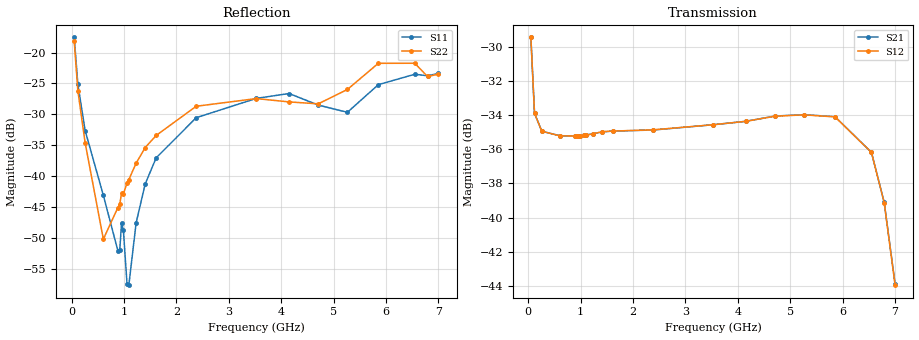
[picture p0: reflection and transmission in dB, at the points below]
! Integrated Device Technology
! Corporate Headquarters
! 6024 Silver Creek Valley Road
! San Jose, CA 95138  USA
! Phone:  1-408-284-8200
! Toll Free:  1-800-223-1366
! Webpage:  http://www.idt.com/
! Timing and RF Division
! 515 Groton Road, Suite 102
! Westford, MA 01886-6024
! Device:  F2258
! Description: Voltage Variable RF Attenuator
! Frequency:  50.0 -  6000.00 MHz
! Package:  3x3 mm Thin QFN Plastic Package: 16 pin
! Ports:  2 RF, 2 DC
!  Pin  1  = NC
!  Pin  2  = NC
!  Pin  3  = RF2  = Port 2
!  Pin  4  = GND
!  Pin  5  = Vdd
!  Pin  6  = NC
!  Pin  7  = VCTRL
!  Pin  8  = NC
!  Pin  9  = GND
!  Pin 10  = RF1  = Port 1
!  Pin 11  = NC
!  Pin 12  = NC
!  Pin 13  = NC
!  Pin 14  = NC
!  Pin 15  = NC
!  Pin 16  = NC
! Vcntrl:  2.090 Volts
! Vdd:  +3.300 Volts
! Current:  1.150 mA
! Data:  The device was measured on a the F2258 evaluation board which has
!  individual transmission lines to the RF pins.  Data was collected
!  using a calibrated network analyzer.  The evaluation board was
!  de-embedded using a TRL calibration technique.
!  The reference plane is the edge of the package pin.
! Misc:  SN 10
!  Action Tracker AT0285
! Date Measured:  2014-12-10
! Date:  2016-01-13  MJV
! Note:
!  Integrated Device Technology supplies this data as a sample of measured
!  data at the package pin for this product.  Your particular data for this
!  product may vary.
!  Data was taken at 25 degrees C.
!  Integrated Device Technology reserves the right to change this data at anytime.
!Freq_(GHz)  S11M_(dB)  S11P_(deg)  S21M_(dB)  S21P_(deg)  S12M_(dB)  S12P_(deg)  S22M_(dB)  S22P_(deg)
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# GHz S dB R 50
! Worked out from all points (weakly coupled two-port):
!   201 points, 50 MHz to 7 GHz, reference 50 ohm
!   highest |S21| = -29.44 dB at 50 MHz (marker M1); lowest = -43.9 dB at 7 GHz (marker M2)
!   lowest |S11| = -57.6 dB at 1.093 GHz (marker M3), VSWR 1.00, Z = 49.9 + j0.114 ohm
!   |S11| at or under -10 dB: start of sweep to end of sweep
!   |S22| runs from -50.2 to -18.2 dB; largest |S21 - S12| = 7.9e-05
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0.05  -17.55 -111.0  -29.44 -67.6  -29.44 -67.6  -18.16 -109.8
0.1195  -25.11 -106.8  -33.89 -36.3  -33.89 -36.3  -26.16 -100.6
0.2585  -32.61 -111.9  -34.94 -18.6  -34.94 -18.6  -34.58 -94.6
0.606  -43.08 -126.1  -35.21 -10.0  -35.21 -10.0  -50.16 -13.7
0.884  -52.05 165.8  -35.21 -8.5  -35.22 -8.5  -45.05 52.2
0.91875  -51.99 150.3  -35.21 -8.5  -35.21 -8.4  -44.54 54.7
0.9535  -47.53 -162.4  -35.22 -8.4  -35.22 -8.4  -42.76 82.3
0.98825  -48.71 -174.0  -35.20 -8.3  -35.20 -8.3  -42.86 78.0
1.05775  -57.39 154.7  -35.18 -8.1  -35.19 -8.1  -41.09 64.8
1.0925  -57.59 119.8  -35.17 -8.1  -35.17 -8.1  -40.53 62.3
1.2315  -47.53 46.2  -35.09 -8.1  -35.10 -8.2  -37.88 48.9
1.40525  -41.22 33.8  -34.98 -8.8  -34.97 -8.8  -35.35 43.7
1.61375  -37.02 32.8  -34.93 -9.9  -34.93 -9.9  -33.40 36.0
2.37825  -30.53 48.2  -34.87 -13.6  -34.86 -13.6  -28.68 33.4
3.525  -27.41 91.6  -34.56 -20.2  -34.56 -20.2  -27.44 60.0
4.1505  -26.62 104.9  -34.36 -24.7  -34.36 -24.7  -27.98 69.1
4.7065  -28.49 95.6  -34.05 -29.4  -34.06 -29.4  -28.29 51.6
5.2625  -29.66 54.3  -33.97 -35.5  -33.98 -35.6  -25.97 14.4
5.85325  -25.19 29.9  -34.09 -46.0  -34.10 -46.0  -21.74 -6.8
6.54825  -23.51 45.0  -36.18 -66.4  -36.18 -66.5  -21.73 -41.2
6.7915  -23.75 63.2  -39.11 -73.2  -39.12 -73.1  -23.87 -76.3
7  -23.38 84.4  -43.90 -62.0  -43.96 -61.4  -23.50 -128.8
